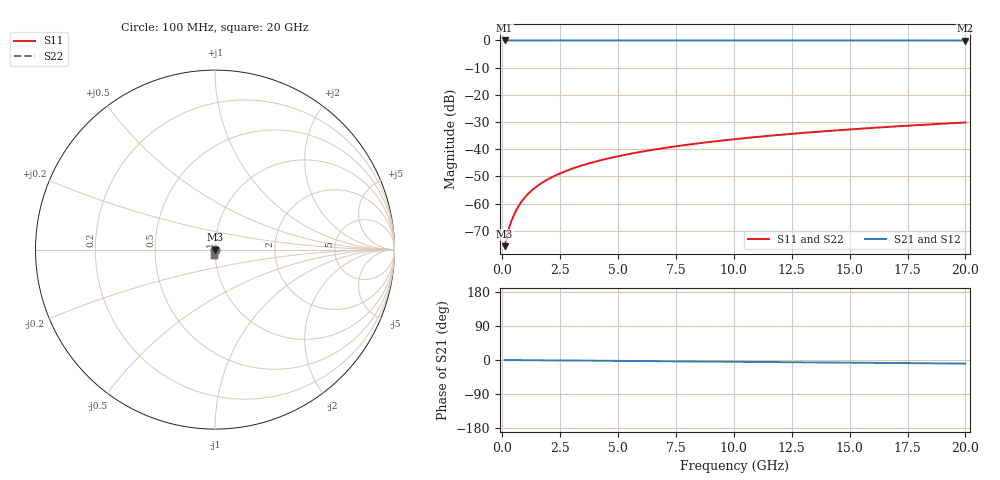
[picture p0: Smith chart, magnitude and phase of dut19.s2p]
! Touchstone file exported from HFSS 2026.1.0
!  File:  C:/ffzhzh/LocalFiles/Ansys_Project_Files/temp_test_TSV_19_1782978396_45748.aedt
!  Generated:  03:47:50 PM Jul  2, 2026
!  Design:  TSV
!  Project:  temp_test_TSV_19_1782978396_45748
! Variables:
!  h_bsmrdl = 2um
!  h_ox = 20um
!  h_rdl = 5um
!  h_sub = 97.25um
!  h_tmrdl = 5um
!  h_tsv = 97.25um
!  h_via = 3um
!  l_bsmrdl = 300um
!  l_sub = 422.36um
!  l_tmrdl = 200um
!  m_sub = 200um
!  pitch = 37.7um
!  r_tsv = 11.18um
!  s_tmrdl = 10um
!  w_bsmrdl = 18um
!  w_sub = 500um
!  w_tmrdl = 12um
!  x_tsv_center1 = 206um
!  x_tsv_center2 = 524um
!  x_tsv_center3 = 736um
!  x_tsv_center4 = 1054um
!  x_tsv_center5 = 1266um
!  x_tsv_center6 = 1584um
# GHz S MA R 50.000000
! Terminal data exported
! Port[1] = TSV1_1_T1
! Port[2] = TSV1_1_T2
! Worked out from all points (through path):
!   200 points, 100 MHz to 20 GHz, reference 50 ohm
!   highest |S21| = 0.00 dB at 100 MHz (marker M1); lowest = 0.0 dB at 20 GHz (marker M2)
!   group delay of S21, straight-line fit = 1.3 ps
!   lowest |S11| = -75.7 dB at 100 MHz (marker M3), VSWR 1.00, Z = 50 - j0.0102 ohm
!   |S11| at or under -10 dB: start of sweep to end of sweep
!   |S22| runs from -75.7 to -30.2 dB; largest |S21 - S12| = 2.1e-15
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0.1  0.0001647 -38.1  0.9999 -0.1  0.9999 -0.1  0.0001647 -38.1
! Gamma 0 0 0 0
! Port Impedance 50 0 50 0
0.2  0.0002532 -54.9  0.9999 -0.1  0.9999 -0.1  0.0002532 -54.9
0.3  0.0003618 -62.1  0.9998 -0.1  0.9998 -0.1  0.0003618 -62.1
0.4  0.0004827 -65.9  0.9998 -0.2  0.9998 -0.2  0.0004827 -65.9
0.5  0.0006128 -68.3  0.9998 -0.2  0.9998 -0.2  0.0006128 -68.3
0.6  0.0007497 -70.1  0.9997 -0.3  0.9997 -0.3  0.0007497 -70.1
0.8  0.001037 -72.9  0.9997 -0.4  0.9997 -0.4  0.001037 -72.9
1.1  0.001483 -75.9  0.9996 -0.5  0.9996 -0.5  0.001483 -75.9
1.3  0.001784 -77.5  0.9996 -0.6  0.9996 -0.6  0.001784 -77.5
1.5  0.002086 -78.8  0.9996 -0.7  0.9996 -0.7  0.002086 -78.8
1.8  0.002539 -80.3  0.9995 -0.9  0.9995 -0.9  0.002539 -80.3
2.1  0.002993 -81.5  0.9995 -1.0  0.9995 -1.0  0.002993 -81.5
2.7  0.003901 -83.2  0.9994 -1.3  0.9994 -1.3  0.003901 -83.2
3.5  0.005117 -84.7  0.9994 -1.7  0.9994 -1.7  0.005117 -84.7
4.2  0.006189 -85.7  0.9993 -2.0  0.9993 -2.0  0.006189 -85.7
5  0.007422 -86.6  0.9992 -2.4  0.9992 -2.4  0.007422 -86.7
6.8  0.01022 -88.3  0.9991 -3.2  0.9991 -3.2  0.01022 -88.3
8.3  0.01257 -89.5  0.999 -3.9  0.999 -3.9  0.01257 -89.5
10.1  0.0154 -90.8  0.9988 -4.8  0.9988 -4.8  0.0154 -90.8
13.4  0.02059 -92.9  0.9986 -6.3  0.9986 -6.3  0.02059 -92.9
16.7  0.02579 -94.8  0.9983 -7.8  0.9983 -7.8  0.02579 -94.8
20  0.031 -96.6  0.998 -9.4  0.998 -9.4  0.031 -96.6
